VERSION 5.7 ;
  NOWIREEXTENSIONATPIN ON ;
  DIVIDERCHAR "/" ;
  BUSBITCHARS "[]" ;
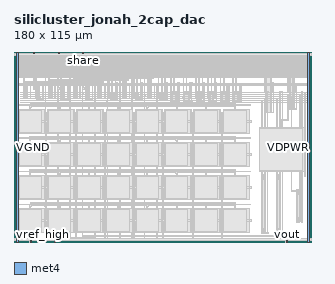
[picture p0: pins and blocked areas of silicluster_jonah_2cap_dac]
MACRO silicluster_jonah_2cap_dac
  CLASS BLOCK ;
  FOREIGN silicluster_jonah_2cap_dac ;
  ORIGIN 0.000 0.000 ;
  SIZE 180.000 BY 115.000 ;
  PIN VGND
    DIRECTION INPUT ;
    USE GROUND ;
    PORT
      LAYER met4 ;
        RECT 1.400 0.000 2.600 115.000 ;
    END
  END VGND
  PIN VDPWR
    DIRECTION INPUT ;
    USE POWER ;
    PORT
      LAYER met4 ;
        RECT 177.400 0.000 178.600 115.000 ;
    END
  END VDPWR
  PIN charge_high
    DIRECTION INPUT ;
    USE SIGNAL ;
    ANTENNAGATEAREA 0.600000 ;
    PORT
      LAYER met4 ;
        RECT 11.700 114.200 12.300 115.000 ;
    END
  END charge_high
  PIN charge_low
    DIRECTION INPUT ;
    USE SIGNAL ;
    ANTENNAGATEAREA 0.600000 ;
    PORT
      LAYER met4 ;
        RECT 26.700 114.200 27.300 115.000 ;
    END
  END charge_low
  PIN share
    DIRECTION INPUT ;
    USE SIGNAL ;
    ANTENNAGATEAREA 0.600000 ;
    PORT
      LAYER met4 ;
        RECT 41.700 114.200 42.300 115.000 ;
    END
  END share
  PIN vref_high
    DIRECTION INPUT ;
    USE SIGNAL ;
    ANTENNADIFFAREA 0.870000 ;
    PORT
      LAYER met4 ;
        RECT 9.700 0.000 10.300 0.800 ;
    END
  END vref_high
  PIN vref_low
    DIRECTION INPUT ;
    USE SIGNAL ;
    ANTENNADIFFAREA 0.870000 ;
    PORT
      LAYER met4 ;
        RECT 24.700 0.000 25.300 0.800 ;
    END
  END vref_low
  PIN vout
    DIRECTION OUTPUT ;
    USE SIGNAL ;
    ANTENNAGATEAREA 4.000000 ;
    ANTENNADIFFAREA 12.759999 ;
    PORT
      LAYER met4 ;
        RECT 164.700 0.000 165.300 0.800 ;
    END
  END vout
  OBS
      LAYER pwell ;
        RECT 5.945 86.605 8.055 89.395 ;
      LAYER nwell ;
        RECT 13.445 86.080 15.555 89.920 ;
      LAYER pwell ;
        RECT 20.945 86.605 23.055 89.395 ;
      LAYER nwell ;
        RECT 28.445 86.080 30.555 89.920 ;
      LAYER pwell ;
        RECT 35.945 86.605 38.055 89.395 ;
      LAYER nwell ;
        RECT 43.445 86.080 45.555 89.920 ;
      LAYER pwell ;
        RECT 50.945 86.605 53.055 89.395 ;
      LAYER nwell ;
        RECT 58.345 86.080 60.655 89.920 ;
      LAYER pwell ;
        RECT 65.945 86.605 68.055 89.395 ;
      LAYER nwell ;
        RECT 73.345 86.080 75.655 89.920 ;
      LAYER pwell ;
        RECT 80.945 86.605 83.055 89.395 ;
      LAYER nwell ;
        RECT 88.345 86.080 90.655 89.920 ;
        RECT 95.020 85.080 98.980 90.920 ;
        RECT 102.520 85.080 106.480 90.920 ;
        RECT 110.520 85.080 113.480 90.920 ;
        RECT 118.020 85.080 120.980 90.920 ;
      LAYER pwell ;
        RECT 125.020 85.105 128.980 90.895 ;
        RECT 132.520 85.105 136.480 90.895 ;
      LAYER nwell ;
        RECT 152.020 78.080 155.980 103.920 ;
      LAYER pwell ;
        RECT 166.520 80.105 169.480 101.895 ;
        RECT 149.995 5.090 152.005 40.910 ;
        RECT 158.995 5.090 161.005 40.910 ;
        RECT 170.995 12.090 173.005 31.910 ;
      LAYER li1 ;
        RECT 152.200 103.570 155.800 103.740 ;
        RECT 95.200 90.570 98.800 90.740 ;
        RECT 13.625 89.570 15.375 89.740 ;
        RECT 6.125 89.045 7.875 89.215 ;
        RECT 6.125 86.955 6.295 89.045 ;
        RECT 6.835 88.535 7.165 88.705 ;
        RECT 6.695 87.325 6.865 88.365 ;
        RECT 7.135 87.325 7.305 88.365 ;
        RECT 7.705 86.955 7.875 89.045 ;
        RECT 6.125 86.785 7.875 86.955 ;
        RECT 13.625 86.430 13.795 89.570 ;
        RECT 14.335 89.055 14.665 89.225 ;
        RECT 14.195 86.800 14.365 88.840 ;
        RECT 14.635 86.800 14.805 88.840 ;
        RECT 15.205 86.430 15.375 89.570 ;
        RECT 28.625 89.570 30.375 89.740 ;
        RECT 21.125 89.045 22.875 89.215 ;
        RECT 21.125 86.955 21.295 89.045 ;
        RECT 21.835 88.535 22.165 88.705 ;
        RECT 21.695 87.325 21.865 88.365 ;
        RECT 22.135 87.325 22.305 88.365 ;
        RECT 22.705 86.955 22.875 89.045 ;
        RECT 21.125 86.785 22.875 86.955 ;
        RECT 13.625 86.260 15.375 86.430 ;
        RECT 28.625 86.430 28.795 89.570 ;
        RECT 29.335 89.055 29.665 89.225 ;
        RECT 29.195 86.800 29.365 88.840 ;
        RECT 29.635 86.800 29.805 88.840 ;
        RECT 30.205 86.430 30.375 89.570 ;
        RECT 43.625 89.570 45.375 89.740 ;
        RECT 36.125 89.045 37.875 89.215 ;
        RECT 36.125 86.955 36.295 89.045 ;
        RECT 36.835 88.535 37.165 88.705 ;
        RECT 36.695 87.325 36.865 88.365 ;
        RECT 37.135 87.325 37.305 88.365 ;
        RECT 37.705 86.955 37.875 89.045 ;
        RECT 36.125 86.785 37.875 86.955 ;
        RECT 28.625 86.260 30.375 86.430 ;
        RECT 43.625 86.430 43.795 89.570 ;
        RECT 44.335 89.055 44.665 89.225 ;
        RECT 44.195 86.800 44.365 88.840 ;
        RECT 44.635 86.800 44.805 88.840 ;
        RECT 45.205 86.430 45.375 89.570 ;
        RECT 58.525 89.570 60.475 89.740 ;
        RECT 51.125 89.045 52.875 89.215 ;
        RECT 51.125 86.955 51.295 89.045 ;
        RECT 51.835 88.535 52.165 88.705 ;
        RECT 51.695 87.325 51.865 88.365 ;
        RECT 52.135 87.325 52.305 88.365 ;
        RECT 52.705 86.955 52.875 89.045 ;
        RECT 51.125 86.785 52.875 86.955 ;
        RECT 43.625 86.260 45.375 86.430 ;
        RECT 58.525 86.430 58.695 89.570 ;
        RECT 59.325 89.055 59.675 89.225 ;
        RECT 59.095 86.800 59.265 88.840 ;
        RECT 59.735 86.800 59.905 88.840 ;
        RECT 60.305 86.430 60.475 89.570 ;
        RECT 73.525 89.570 75.475 89.740 ;
        RECT 66.125 89.045 67.875 89.215 ;
        RECT 66.125 86.955 66.295 89.045 ;
        RECT 66.835 88.535 67.165 88.705 ;
        RECT 66.695 87.325 66.865 88.365 ;
        RECT 67.135 87.325 67.305 88.365 ;
        RECT 67.705 86.955 67.875 89.045 ;
        RECT 66.125 86.785 67.875 86.955 ;
        RECT 58.525 86.260 60.475 86.430 ;
        RECT 73.525 86.430 73.695 89.570 ;
        RECT 74.325 89.055 74.675 89.225 ;
        RECT 74.095 86.800 74.265 88.840 ;
        RECT 74.735 86.800 74.905 88.840 ;
        RECT 75.305 86.430 75.475 89.570 ;
        RECT 88.525 89.570 90.475 89.740 ;
        RECT 81.125 89.045 82.875 89.215 ;
        RECT 81.125 86.955 81.295 89.045 ;
        RECT 81.835 88.535 82.165 88.705 ;
        RECT 81.695 87.325 81.865 88.365 ;
        RECT 82.135 87.325 82.305 88.365 ;
        RECT 82.705 86.955 82.875 89.045 ;
        RECT 81.125 86.785 82.875 86.955 ;
        RECT 73.525 86.260 75.475 86.430 ;
        RECT 88.525 86.430 88.695 89.570 ;
        RECT 89.325 89.055 89.675 89.225 ;
        RECT 89.095 86.800 89.265 88.840 ;
        RECT 89.735 86.800 89.905 88.840 ;
        RECT 90.305 86.430 90.475 89.570 ;
        RECT 88.525 86.260 90.475 86.430 ;
        RECT 95.200 85.430 95.370 90.570 ;
        RECT 96.000 90.055 98.000 90.225 ;
        RECT 95.770 85.800 95.940 89.840 ;
        RECT 98.060 85.800 98.230 89.840 ;
        RECT 98.630 85.430 98.800 90.570 ;
        RECT 95.200 85.260 98.800 85.430 ;
        RECT 102.700 90.570 106.300 90.740 ;
        RECT 102.700 85.430 102.870 90.570 ;
        RECT 103.500 90.055 105.500 90.225 ;
        RECT 103.270 85.800 103.440 89.840 ;
        RECT 105.560 85.800 105.730 89.840 ;
        RECT 106.130 85.430 106.300 90.570 ;
        RECT 102.700 85.260 106.300 85.430 ;
        RECT 110.700 90.570 113.300 90.740 ;
        RECT 110.700 85.430 110.870 90.570 ;
        RECT 111.500 90.055 112.500 90.225 ;
        RECT 111.270 85.800 111.440 89.840 ;
        RECT 112.560 85.800 112.730 89.840 ;
        RECT 113.130 85.430 113.300 90.570 ;
        RECT 110.700 85.260 113.300 85.430 ;
        RECT 118.200 90.570 120.800 90.740 ;
        RECT 118.200 85.430 118.370 90.570 ;
        RECT 119.000 90.055 120.000 90.225 ;
        RECT 118.770 85.800 118.940 89.840 ;
        RECT 120.060 85.800 120.230 89.840 ;
        RECT 120.630 85.430 120.800 90.570 ;
        RECT 118.200 85.260 120.800 85.430 ;
        RECT 125.200 90.545 128.800 90.715 ;
        RECT 125.200 85.455 125.370 90.545 ;
        RECT 126.000 90.035 128.000 90.205 ;
        RECT 125.770 85.825 125.940 89.865 ;
        RECT 128.060 85.825 128.230 89.865 ;
        RECT 128.630 85.455 128.800 90.545 ;
        RECT 125.200 85.285 128.800 85.455 ;
        RECT 132.700 90.545 136.300 90.715 ;
        RECT 132.700 85.455 132.870 90.545 ;
        RECT 133.500 90.035 135.500 90.205 ;
        RECT 133.270 85.825 133.440 89.865 ;
        RECT 135.560 85.825 135.730 89.865 ;
        RECT 136.130 85.455 136.300 90.545 ;
        RECT 132.700 85.285 136.300 85.455 ;
        RECT 152.200 78.430 152.370 103.570 ;
        RECT 153.000 103.055 155.000 103.225 ;
        RECT 152.770 78.800 152.940 102.840 ;
        RECT 155.060 78.800 155.230 102.840 ;
        RECT 155.630 78.430 155.800 103.570 ;
        RECT 166.700 101.545 169.300 101.715 ;
        RECT 166.700 80.455 166.870 101.545 ;
        RECT 167.500 101.035 168.500 101.205 ;
        RECT 167.270 80.825 167.440 100.865 ;
        RECT 168.560 80.825 168.730 100.865 ;
        RECT 169.130 80.455 169.300 101.545 ;
        RECT 166.700 80.285 169.300 80.455 ;
        RECT 152.200 78.260 155.800 78.430 ;
        RECT 150.175 40.560 151.825 40.730 ;
        RECT 150.175 5.440 150.345 40.560 ;
        RECT 150.825 37.920 151.175 40.080 ;
        RECT 150.825 5.920 151.175 8.080 ;
        RECT 151.655 5.440 151.825 40.560 ;
        RECT 150.175 5.270 151.825 5.440 ;
        RECT 159.175 40.560 160.825 40.730 ;
        RECT 159.175 5.440 159.345 40.560 ;
        RECT 159.825 37.920 160.175 40.080 ;
        RECT 159.825 5.920 160.175 8.080 ;
        RECT 160.655 5.440 160.825 40.560 ;
        RECT 171.175 31.560 172.825 31.730 ;
        RECT 171.175 12.440 171.345 31.560 ;
        RECT 171.825 28.920 172.175 31.080 ;
        RECT 171.825 12.920 172.175 15.080 ;
        RECT 172.655 12.440 172.825 31.560 ;
        RECT 171.175 12.270 172.825 12.440 ;
        RECT 159.175 5.270 160.825 5.440 ;
      LAYER met1 ;
        RECT 41.250 113.750 41.750 114.250 ;
        RECT 26.250 106.750 26.750 107.250 ;
        RECT 18.750 104.750 19.250 105.250 ;
        RECT 14.250 89.490 14.750 89.990 ;
        RECT 6.750 88.970 7.250 89.470 ;
        RECT 14.370 89.255 14.630 89.490 ;
        RECT 14.355 89.025 14.645 89.255 ;
        RECT 14.370 89.010 14.630 89.025 ;
        RECT 6.870 88.735 7.130 88.970 ;
        RECT 6.855 88.505 7.145 88.735 ;
        RECT 6.870 88.490 7.130 88.505 ;
        RECT 5.750 87.985 6.250 88.095 ;
        RECT 6.665 87.985 6.895 88.345 ;
        RECT 7.105 87.985 7.335 88.345 ;
        RECT 7.750 87.985 8.250 88.095 ;
        RECT 5.750 87.705 6.920 87.985 ;
        RECT 7.080 87.705 8.250 87.985 ;
        RECT 5.750 87.595 6.250 87.705 ;
        RECT 6.665 87.345 6.895 87.705 ;
        RECT 7.105 87.345 7.335 87.705 ;
        RECT 7.750 87.595 8.250 87.705 ;
        RECT 13.250 87.960 13.750 88.070 ;
        RECT 14.165 87.960 14.395 88.820 ;
        RECT 14.605 87.960 14.835 88.820 ;
        RECT 15.250 87.960 15.750 88.070 ;
        RECT 13.250 87.680 14.420 87.960 ;
        RECT 14.580 87.680 15.750 87.960 ;
        RECT 13.250 87.570 13.750 87.680 ;
        RECT 6.750 87.010 7.250 87.120 ;
        RECT 9.750 87.010 10.250 87.120 ;
        RECT 6.750 86.730 10.250 87.010 ;
        RECT 14.165 86.820 14.395 87.680 ;
        RECT 14.605 86.820 14.835 87.680 ;
        RECT 15.250 87.570 15.750 87.680 ;
        RECT 6.750 86.620 7.250 86.730 ;
        RECT 9.750 86.620 10.250 86.730 ;
        RECT 14.250 86.485 14.750 86.595 ;
        RECT 17.250 86.485 17.750 86.595 ;
        RECT 14.250 86.205 17.750 86.485 ;
        RECT 14.250 86.095 14.750 86.205 ;
        RECT 17.250 86.095 17.750 86.205 ;
        RECT 18.800 82.250 19.200 104.750 ;
        RECT 21.750 88.970 22.250 89.470 ;
        RECT 21.870 88.735 22.130 88.970 ;
        RECT 21.855 88.505 22.145 88.735 ;
        RECT 21.870 88.490 22.130 88.505 ;
        RECT 20.750 87.985 21.250 88.095 ;
        RECT 21.665 87.985 21.895 88.345 ;
        RECT 22.105 87.985 22.335 88.345 ;
        RECT 22.750 87.985 23.250 88.095 ;
        RECT 20.750 87.705 21.920 87.985 ;
        RECT 22.080 87.705 23.250 87.985 ;
        RECT 20.750 87.595 21.250 87.705 ;
        RECT 21.665 87.345 21.895 87.705 ;
        RECT 22.105 87.345 22.335 87.705 ;
        RECT 22.750 87.595 23.250 87.705 ;
        RECT 21.750 87.010 22.250 87.120 ;
        RECT 24.750 87.010 25.250 87.120 ;
        RECT 21.750 86.730 25.250 87.010 ;
        RECT 21.750 86.620 22.250 86.730 ;
        RECT 24.750 86.620 25.250 86.730 ;
        RECT 26.300 83.750 26.700 106.750 ;
        RECT 33.750 102.750 34.250 103.250 ;
        RECT 29.250 89.490 29.750 89.990 ;
        RECT 29.370 89.255 29.630 89.490 ;
        RECT 29.355 89.025 29.645 89.255 ;
        RECT 29.370 89.010 29.630 89.025 ;
        RECT 28.250 87.960 28.750 88.070 ;
        RECT 29.165 87.960 29.395 88.820 ;
        RECT 29.605 87.960 29.835 88.820 ;
        RECT 30.250 87.960 30.750 88.070 ;
        RECT 28.250 87.680 29.420 87.960 ;
        RECT 29.580 87.680 30.750 87.960 ;
        RECT 28.250 87.570 28.750 87.680 ;
        RECT 29.165 86.820 29.395 87.680 ;
        RECT 29.605 86.820 29.835 87.680 ;
        RECT 30.250 87.570 30.750 87.680 ;
        RECT 29.250 86.485 29.750 86.595 ;
        RECT 32.250 86.485 32.750 86.595 ;
        RECT 29.250 86.205 32.750 86.485 ;
        RECT 29.250 86.095 29.750 86.205 ;
        RECT 32.250 86.095 32.750 86.205 ;
        RECT 26.250 83.250 26.750 83.750 ;
        RECT 18.750 81.750 19.250 82.250 ;
        RECT 18.800 62.250 19.200 81.750 ;
        RECT 26.300 63.750 26.700 83.250 ;
        RECT 26.250 63.250 26.750 63.750 ;
        RECT 18.750 61.750 19.250 62.250 ;
        RECT 18.800 42.250 19.200 61.750 ;
        RECT 26.300 43.750 26.700 63.250 ;
        RECT 26.250 43.250 26.750 43.750 ;
        RECT 18.750 41.750 19.250 42.250 ;
        RECT 18.800 22.250 19.200 41.750 ;
        RECT 26.300 23.750 26.700 43.250 ;
        RECT 26.250 23.250 26.750 23.750 ;
        RECT 18.750 21.750 19.250 22.250 ;
        RECT 18.800 1.000 19.200 21.750 ;
        RECT 26.300 1.000 26.700 23.250 ;
        RECT 33.800 2.050 34.200 102.750 ;
        RECT 41.300 89.550 41.700 113.750 ;
        RECT 78.750 112.750 79.250 113.250 ;
        RECT 71.250 111.750 71.750 112.250 ;
        RECT 63.750 108.750 64.250 109.250 ;
        RECT 56.250 107.750 56.750 108.250 ;
        RECT 48.750 103.750 49.250 104.250 ;
        RECT 36.750 88.970 37.250 89.470 ;
        RECT 41.250 89.050 41.750 89.550 ;
        RECT 44.250 89.490 44.750 89.990 ;
        RECT 44.370 89.255 44.630 89.490 ;
        RECT 36.870 88.735 37.130 88.970 ;
        RECT 36.855 88.505 37.145 88.735 ;
        RECT 36.870 88.490 37.130 88.505 ;
        RECT 35.750 87.985 36.250 88.095 ;
        RECT 36.665 87.985 36.895 88.345 ;
        RECT 37.105 87.985 37.335 88.345 ;
        RECT 37.750 87.985 38.250 88.095 ;
        RECT 35.750 87.705 36.920 87.985 ;
        RECT 37.080 87.705 38.250 87.985 ;
        RECT 35.750 87.595 36.250 87.705 ;
        RECT 36.665 87.345 36.895 87.705 ;
        RECT 37.105 87.345 37.335 87.705 ;
        RECT 37.750 87.595 38.250 87.705 ;
        RECT 36.750 87.010 37.250 87.120 ;
        RECT 39.750 87.010 40.250 87.120 ;
        RECT 36.750 86.730 40.250 87.010 ;
        RECT 36.750 86.620 37.250 86.730 ;
        RECT 39.750 86.620 40.250 86.730 ;
        RECT 41.300 4.050 41.700 89.050 ;
        RECT 44.355 89.025 44.645 89.255 ;
        RECT 44.370 89.010 44.630 89.025 ;
        RECT 43.250 87.960 43.750 88.070 ;
        RECT 44.165 87.960 44.395 88.820 ;
        RECT 44.605 87.960 44.835 88.820 ;
        RECT 45.250 87.960 45.750 88.070 ;
        RECT 43.250 87.680 44.420 87.960 ;
        RECT 44.580 87.680 45.750 87.960 ;
        RECT 43.250 87.570 43.750 87.680 ;
        RECT 44.165 86.820 44.395 87.680 ;
        RECT 44.605 86.820 44.835 87.680 ;
        RECT 45.250 87.570 45.750 87.680 ;
        RECT 44.250 86.485 44.750 86.595 ;
        RECT 47.250 86.485 47.750 86.595 ;
        RECT 44.250 86.205 47.750 86.485 ;
        RECT 44.250 86.095 44.750 86.205 ;
        RECT 47.250 86.095 47.750 86.205 ;
        RECT 41.250 3.550 41.750 4.050 ;
        RECT 33.750 1.550 34.250 2.050 ;
        RECT 33.800 1.000 34.200 1.550 ;
        RECT 41.300 1.000 41.700 3.550 ;
        RECT 48.800 3.050 49.200 103.750 ;
        RECT 51.750 88.970 52.250 89.470 ;
        RECT 51.870 88.735 52.130 88.970 ;
        RECT 51.855 88.505 52.145 88.735 ;
        RECT 51.870 88.490 52.130 88.505 ;
        RECT 50.750 87.985 51.250 88.095 ;
        RECT 51.665 87.985 51.895 88.345 ;
        RECT 52.105 87.985 52.335 88.345 ;
        RECT 52.750 87.985 53.250 88.095 ;
        RECT 50.750 87.705 51.920 87.985 ;
        RECT 52.080 87.705 53.250 87.985 ;
        RECT 50.750 87.595 51.250 87.705 ;
        RECT 51.665 87.345 51.895 87.705 ;
        RECT 52.105 87.345 52.335 87.705 ;
        RECT 52.750 87.595 53.250 87.705 ;
        RECT 51.750 87.010 52.250 87.120 ;
        RECT 54.750 87.010 55.250 87.120 ;
        RECT 51.750 86.730 55.250 87.010 ;
        RECT 51.750 86.620 52.250 86.730 ;
        RECT 54.750 86.620 55.250 86.730 ;
        RECT 56.300 84.750 56.700 107.750 ;
        RECT 59.250 89.490 59.750 89.990 ;
        RECT 59.370 89.255 59.630 89.490 ;
        RECT 59.345 89.025 59.655 89.255 ;
        RECT 59.370 89.010 59.630 89.025 ;
        RECT 57.250 87.960 57.750 88.070 ;
        RECT 59.065 87.960 59.295 88.820 ;
        RECT 59.705 87.960 59.935 88.820 ;
        RECT 61.250 87.960 61.750 88.070 ;
        RECT 57.250 87.680 59.320 87.960 ;
        RECT 59.680 87.680 61.750 87.960 ;
        RECT 57.250 87.570 57.750 87.680 ;
        RECT 59.065 86.820 59.295 87.680 ;
        RECT 59.705 86.820 59.935 87.680 ;
        RECT 61.250 87.570 61.750 87.680 ;
        RECT 59.250 86.485 59.750 86.595 ;
        RECT 62.250 86.485 62.750 86.595 ;
        RECT 59.250 86.205 62.750 86.485 ;
        RECT 59.250 86.095 59.750 86.205 ;
        RECT 62.250 86.095 62.750 86.205 ;
        RECT 63.800 85.950 64.200 108.750 ;
        RECT 66.750 88.970 67.250 89.470 ;
        RECT 66.870 88.735 67.130 88.970 ;
        RECT 66.855 88.505 67.145 88.735 ;
        RECT 66.870 88.490 67.130 88.505 ;
        RECT 65.750 87.985 66.250 88.095 ;
        RECT 66.665 87.985 66.895 88.345 ;
        RECT 67.105 87.985 67.335 88.345 ;
        RECT 67.750 87.985 68.250 88.095 ;
        RECT 65.750 87.705 66.920 87.985 ;
        RECT 67.080 87.705 68.250 87.985 ;
        RECT 65.750 87.595 66.250 87.705 ;
        RECT 66.665 87.345 66.895 87.705 ;
        RECT 67.105 87.345 67.335 87.705 ;
        RECT 67.750 87.595 68.250 87.705 ;
        RECT 71.300 87.150 71.700 111.750 ;
        RECT 74.250 89.490 74.750 89.990 ;
        RECT 74.370 89.255 74.630 89.490 ;
        RECT 74.345 89.025 74.655 89.255 ;
        RECT 74.370 89.010 74.630 89.025 ;
        RECT 72.250 87.960 72.750 88.070 ;
        RECT 74.065 87.960 74.295 88.820 ;
        RECT 74.705 87.960 74.935 88.820 ;
        RECT 78.800 88.350 79.200 112.750 ;
        RECT 153.750 103.490 154.250 103.990 ;
        RECT 153.870 103.255 154.130 103.490 ;
        RECT 153.020 103.025 154.980 103.255 ;
        RECT 153.870 103.010 154.130 103.025 ;
        RECT 86.250 94.750 86.750 95.250 ;
        RECT 86.300 90.750 86.700 94.750 ;
        RECT 86.250 90.250 86.750 90.750 ;
        RECT 96.750 90.490 97.250 90.990 ;
        RECT 104.250 90.490 104.750 90.990 ;
        RECT 111.750 90.490 112.250 90.990 ;
        RECT 119.250 90.490 119.750 90.990 ;
        RECT 96.870 90.255 97.130 90.490 ;
        RECT 104.370 90.255 104.630 90.490 ;
        RECT 111.870 90.255 112.130 90.490 ;
        RECT 119.370 90.255 119.630 90.490 ;
        RECT 126.750 90.470 127.250 90.970 ;
        RECT 134.250 90.470 134.750 90.970 ;
        RECT 151.750 90.960 152.250 91.070 ;
        RECT 152.740 90.960 152.970 102.820 ;
        RECT 155.030 90.960 155.260 102.820 ;
        RECT 167.750 101.470 168.250 101.970 ;
        RECT 167.870 101.235 168.130 101.470 ;
        RECT 167.520 101.005 168.480 101.235 ;
        RECT 167.870 100.990 168.130 101.005 ;
        RECT 155.750 90.960 156.250 91.070 ;
        RECT 151.750 90.680 152.995 90.960 ;
        RECT 155.005 90.680 156.250 90.960 ;
        RECT 151.750 90.570 152.250 90.680 ;
        RECT 81.750 88.970 82.250 89.470 ;
        RECT 81.870 88.735 82.130 88.970 ;
        RECT 81.855 88.505 82.145 88.735 ;
        RECT 81.870 88.490 82.130 88.505 ;
        RECT 76.250 87.960 76.750 88.070 ;
        RECT 72.250 87.680 74.320 87.960 ;
        RECT 74.680 87.680 76.750 87.960 ;
        RECT 78.750 87.850 79.250 88.350 ;
        RECT 80.750 87.985 81.250 88.095 ;
        RECT 81.665 87.985 81.895 88.345 ;
        RECT 82.105 87.985 82.335 88.345 ;
        RECT 82.750 87.985 83.250 88.095 ;
        RECT 72.250 87.570 72.750 87.680 ;
        RECT 66.750 87.010 67.250 87.120 ;
        RECT 69.750 87.010 70.250 87.120 ;
        RECT 66.750 86.730 70.250 87.010 ;
        RECT 66.750 86.620 67.250 86.730 ;
        RECT 69.750 86.620 70.250 86.730 ;
        RECT 71.250 86.650 71.750 87.150 ;
        RECT 74.065 86.820 74.295 87.680 ;
        RECT 74.705 86.820 74.935 87.680 ;
        RECT 76.250 87.570 76.750 87.680 ;
        RECT 63.750 85.450 64.250 85.950 ;
        RECT 56.250 84.250 56.750 84.750 ;
        RECT 48.750 2.550 49.250 3.050 ;
        RECT 48.800 1.000 49.200 2.550 ;
        RECT 56.300 1.000 56.700 84.250 ;
        RECT 63.800 1.000 64.200 85.450 ;
        RECT 71.300 1.000 71.700 86.650 ;
        RECT 74.250 86.485 74.750 86.595 ;
        RECT 77.250 86.485 77.750 86.595 ;
        RECT 74.250 86.205 77.750 86.485 ;
        RECT 74.250 86.095 74.750 86.205 ;
        RECT 77.250 86.095 77.750 86.205 ;
        RECT 78.800 1.000 79.200 87.850 ;
        RECT 80.750 87.705 81.920 87.985 ;
        RECT 82.080 87.705 83.250 87.985 ;
        RECT 80.750 87.595 81.250 87.705 ;
        RECT 81.665 87.345 81.895 87.705 ;
        RECT 82.105 87.345 82.335 87.705 ;
        RECT 82.750 87.595 83.250 87.705 ;
        RECT 81.750 87.010 82.250 87.120 ;
        RECT 84.750 87.010 85.250 87.120 ;
        RECT 81.750 86.730 85.250 87.010 ;
        RECT 81.750 86.620 82.250 86.730 ;
        RECT 84.750 86.620 85.250 86.730 ;
        RECT 86.300 83.000 86.700 90.250 ;
        RECT 96.020 90.025 97.980 90.255 ;
        RECT 103.520 90.025 105.480 90.255 ;
        RECT 111.520 90.025 112.480 90.255 ;
        RECT 119.020 90.025 119.980 90.255 ;
        RECT 126.870 90.235 127.130 90.470 ;
        RECT 134.370 90.235 134.630 90.470 ;
        RECT 96.870 90.010 97.130 90.025 ;
        RECT 104.370 90.010 104.630 90.025 ;
        RECT 111.870 90.010 112.130 90.025 ;
        RECT 119.370 90.010 119.630 90.025 ;
        RECT 126.020 90.005 127.980 90.235 ;
        RECT 133.520 90.005 135.480 90.235 ;
        RECT 126.870 89.990 127.130 90.005 ;
        RECT 134.370 89.990 134.630 90.005 ;
        RECT 89.250 89.490 89.750 89.990 ;
        RECT 89.370 89.255 89.630 89.490 ;
        RECT 89.345 89.025 89.655 89.255 ;
        RECT 89.370 89.010 89.630 89.025 ;
        RECT 87.250 87.960 87.750 88.070 ;
        RECT 89.065 87.960 89.295 88.820 ;
        RECT 89.705 87.960 89.935 88.820 ;
        RECT 91.250 87.960 91.750 88.070 ;
        RECT 87.250 87.680 89.320 87.960 ;
        RECT 89.680 87.680 91.750 87.960 ;
        RECT 87.250 87.570 87.750 87.680 ;
        RECT 89.065 86.820 89.295 87.680 ;
        RECT 89.705 86.820 89.935 87.680 ;
        RECT 91.250 87.570 91.750 87.680 ;
        RECT 94.750 87.960 95.250 88.070 ;
        RECT 95.740 87.960 95.970 89.820 ;
        RECT 98.030 87.960 98.260 89.820 ;
        RECT 98.750 87.960 99.250 88.070 ;
        RECT 94.750 87.680 95.995 87.960 ;
        RECT 98.005 87.680 99.250 87.960 ;
        RECT 94.750 87.570 95.250 87.680 ;
        RECT 89.250 86.485 89.750 86.595 ;
        RECT 92.250 86.485 92.750 86.595 ;
        RECT 89.250 86.205 92.750 86.485 ;
        RECT 89.250 86.095 89.750 86.205 ;
        RECT 92.250 86.095 92.750 86.205 ;
        RECT 95.740 85.820 95.970 87.680 ;
        RECT 98.030 85.820 98.260 87.680 ;
        RECT 98.750 87.570 99.250 87.680 ;
        RECT 102.250 87.960 102.750 88.070 ;
        RECT 103.240 87.960 103.470 89.820 ;
        RECT 105.530 87.960 105.760 89.820 ;
        RECT 106.250 87.960 106.750 88.070 ;
        RECT 102.250 87.680 103.495 87.960 ;
        RECT 105.505 87.680 106.750 87.960 ;
        RECT 102.250 87.570 102.750 87.680 ;
        RECT 103.240 85.820 103.470 87.680 ;
        RECT 105.530 85.820 105.760 87.680 ;
        RECT 106.250 87.570 106.750 87.680 ;
        RECT 109.750 87.960 110.250 88.070 ;
        RECT 111.240 87.960 111.470 89.820 ;
        RECT 112.530 87.960 112.760 89.820 ;
        RECT 113.750 87.960 114.250 88.070 ;
        RECT 109.750 87.680 111.495 87.960 ;
        RECT 112.505 87.680 114.250 87.960 ;
        RECT 109.750 87.570 110.250 87.680 ;
        RECT 111.240 85.820 111.470 87.680 ;
        RECT 112.530 85.820 112.760 87.680 ;
        RECT 113.750 87.570 114.250 87.680 ;
        RECT 117.250 87.960 117.750 88.070 ;
        RECT 118.740 87.960 118.970 89.820 ;
        RECT 120.030 87.960 120.260 89.820 ;
        RECT 121.250 87.960 121.750 88.070 ;
        RECT 117.250 87.680 118.995 87.960 ;
        RECT 120.005 87.680 121.750 87.960 ;
        RECT 117.250 87.570 117.750 87.680 ;
        RECT 118.740 85.820 118.970 87.680 ;
        RECT 120.030 85.820 120.260 87.680 ;
        RECT 121.250 87.570 121.750 87.680 ;
        RECT 124.750 87.985 125.250 88.095 ;
        RECT 125.740 87.985 125.970 89.845 ;
        RECT 128.030 87.985 128.260 89.845 ;
        RECT 128.750 87.985 129.250 88.095 ;
        RECT 124.750 87.705 125.995 87.985 ;
        RECT 128.005 87.705 129.250 87.985 ;
        RECT 124.750 87.595 125.250 87.705 ;
        RECT 125.740 85.845 125.970 87.705 ;
        RECT 128.030 85.845 128.260 87.705 ;
        RECT 128.750 87.595 129.250 87.705 ;
        RECT 132.250 87.985 132.750 88.095 ;
        RECT 133.240 87.985 133.470 89.845 ;
        RECT 135.530 87.985 135.760 89.845 ;
        RECT 136.250 87.985 136.750 88.095 ;
        RECT 132.250 87.705 133.495 87.985 ;
        RECT 135.505 87.705 136.750 87.985 ;
        RECT 132.250 87.595 132.750 87.705 ;
        RECT 133.240 85.845 133.470 87.705 ;
        RECT 135.530 85.845 135.760 87.705 ;
        RECT 136.250 87.595 136.750 87.705 ;
        RECT 96.750 85.485 97.250 85.595 ;
        RECT 99.750 85.485 100.250 85.595 ;
        RECT 96.750 85.205 100.250 85.485 ;
        RECT 96.750 85.095 97.250 85.205 ;
        RECT 99.750 85.095 100.250 85.205 ;
        RECT 104.250 85.485 104.750 85.595 ;
        RECT 107.250 85.485 107.750 85.595 ;
        RECT 104.250 85.205 107.750 85.485 ;
        RECT 104.250 85.095 104.750 85.205 ;
        RECT 107.250 85.095 107.750 85.205 ;
        RECT 111.750 85.485 112.250 85.595 ;
        RECT 114.750 85.485 115.250 85.595 ;
        RECT 111.750 85.205 115.250 85.485 ;
        RECT 111.750 85.095 112.250 85.205 ;
        RECT 114.750 85.095 115.250 85.205 ;
        RECT 119.250 85.485 119.750 85.595 ;
        RECT 122.250 85.485 122.750 85.595 ;
        RECT 119.250 85.205 122.750 85.485 ;
        RECT 119.250 85.095 119.750 85.205 ;
        RECT 122.250 85.095 122.750 85.205 ;
        RECT 126.750 85.510 127.250 85.620 ;
        RECT 129.750 85.510 130.250 85.620 ;
        RECT 126.750 85.230 130.250 85.510 ;
        RECT 126.750 85.120 127.250 85.230 ;
        RECT 129.750 85.120 130.250 85.230 ;
        RECT 134.250 85.510 134.750 85.620 ;
        RECT 137.250 85.510 137.750 85.620 ;
        RECT 134.250 85.230 137.750 85.510 ;
        RECT 134.250 85.120 134.750 85.230 ;
        RECT 137.250 85.120 137.750 85.230 ;
        RECT 86.250 82.500 86.750 83.000 ;
        RECT 86.300 63.000 86.700 82.500 ;
        RECT 152.740 78.820 152.970 90.680 ;
        RECT 155.030 78.820 155.260 90.680 ;
        RECT 155.750 90.570 156.250 90.680 ;
        RECT 165.750 90.985 166.250 91.095 ;
        RECT 167.240 90.985 167.470 100.845 ;
        RECT 168.530 90.985 168.760 100.845 ;
        RECT 169.750 90.985 170.250 91.095 ;
        RECT 165.750 90.705 167.495 90.985 ;
        RECT 168.505 90.705 170.250 90.985 ;
        RECT 165.750 90.595 166.250 90.705 ;
        RECT 167.240 80.845 167.470 90.705 ;
        RECT 168.530 80.845 168.760 90.705 ;
        RECT 169.750 90.595 170.250 90.705 ;
        RECT 167.750 80.510 168.250 80.620 ;
        RECT 170.750 80.510 171.250 80.620 ;
        RECT 167.750 80.230 171.250 80.510 ;
        RECT 167.750 80.120 168.250 80.230 ;
        RECT 170.750 80.120 171.250 80.230 ;
        RECT 153.750 78.485 154.250 78.595 ;
        RECT 156.750 78.485 157.250 78.595 ;
        RECT 153.750 78.205 157.250 78.485 ;
        RECT 153.750 78.095 154.250 78.205 ;
        RECT 156.750 78.095 157.250 78.205 ;
        RECT 86.250 62.500 86.750 63.000 ;
        RECT 86.300 43.000 86.700 62.500 ;
        RECT 86.250 42.500 86.750 43.000 ;
        RECT 86.300 23.000 86.700 42.500 ;
        RECT 149.750 40.045 150.250 40.155 ;
        RECT 150.875 40.045 151.125 40.050 ;
        RECT 158.750 40.045 159.250 40.155 ;
        RECT 159.875 40.045 160.125 40.050 ;
        RECT 149.750 39.765 151.140 40.045 ;
        RECT 158.750 39.765 160.140 40.045 ;
        RECT 149.750 39.655 150.250 39.765 ;
        RECT 150.875 37.945 151.125 39.765 ;
        RECT 158.750 39.655 159.250 39.765 ;
        RECT 159.875 37.945 160.125 39.765 ;
        RECT 167.750 31.045 168.250 31.155 ;
        RECT 171.875 31.045 172.125 31.050 ;
        RECT 167.750 30.765 172.140 31.045 ;
        RECT 167.750 30.655 168.250 30.765 ;
        RECT 171.875 28.945 172.125 30.765 ;
        RECT 86.250 22.500 86.750 23.000 ;
        RECT 86.300 1.000 86.700 22.500 ;
        RECT 171.875 13.235 172.125 15.055 ;
        RECT 172.750 13.235 173.250 13.345 ;
        RECT 171.860 12.955 173.250 13.235 ;
        RECT 171.875 12.950 172.125 12.955 ;
        RECT 172.750 12.845 173.250 12.955 ;
        RECT 171.750 12.495 172.250 12.605 ;
        RECT 174.250 12.495 174.750 12.605 ;
        RECT 171.750 12.215 174.750 12.495 ;
        RECT 171.750 12.105 172.250 12.215 ;
        RECT 174.250 12.105 174.750 12.215 ;
        RECT 150.875 6.235 151.125 8.055 ;
        RECT 151.750 6.235 152.250 6.345 ;
        RECT 159.875 6.235 160.125 8.055 ;
        RECT 160.750 6.235 161.250 6.345 ;
        RECT 150.860 5.955 152.250 6.235 ;
        RECT 159.860 5.955 161.250 6.235 ;
        RECT 150.875 5.950 151.125 5.955 ;
        RECT 151.750 5.845 152.250 5.955 ;
        RECT 159.875 5.950 160.125 5.955 ;
        RECT 160.750 5.845 161.250 5.955 ;
        RECT 150.750 5.495 151.250 5.605 ;
        RECT 153.250 5.495 153.750 5.605 ;
        RECT 150.750 5.215 153.750 5.495 ;
        RECT 150.750 5.105 151.250 5.215 ;
        RECT 153.250 5.105 153.750 5.215 ;
        RECT 159.750 5.495 160.250 5.605 ;
        RECT 162.250 5.495 162.750 5.605 ;
        RECT 159.750 5.215 162.750 5.495 ;
        RECT 159.750 5.105 160.250 5.215 ;
        RECT 162.250 5.105 162.750 5.215 ;
      LAYER met2 ;
        RECT 41.200 113.700 41.800 114.300 ;
        RECT 119.200 113.700 119.800 114.300 ;
        RECT 151.700 113.700 152.300 114.300 ;
        RECT 165.700 113.700 166.300 114.300 ;
        RECT 78.700 112.700 79.300 113.300 ;
        RECT 71.200 111.700 71.800 112.300 ;
        RECT 109.700 111.700 110.300 112.300 ;
        RECT 102.200 110.700 102.800 111.300 ;
        RECT 63.700 108.700 64.300 109.300 ;
        RECT 56.200 107.700 56.800 108.300 ;
        RECT 94.700 107.700 95.300 108.300 ;
        RECT 96.700 107.700 97.300 108.300 ;
        RECT 26.200 106.700 26.800 107.300 ;
        RECT 82.700 106.700 83.300 107.300 ;
        RECT 91.200 106.700 91.800 107.300 ;
        RECT 18.700 104.700 19.300 105.300 ;
        RECT 52.700 104.700 53.300 105.300 ;
        RECT 61.200 104.700 61.800 105.300 ;
        RECT 67.700 104.700 68.300 105.300 ;
        RECT 76.200 104.700 76.800 105.300 ;
        RECT 80.700 104.700 81.300 105.300 ;
        RECT 48.700 103.700 49.300 104.300 ;
        RECT 33.700 102.700 34.300 103.300 ;
        RECT 50.700 102.700 51.300 103.300 ;
        RECT 35.700 101.700 36.300 102.300 ;
        RECT 43.200 101.700 43.800 102.300 ;
        RECT 20.700 100.700 21.300 101.300 ;
        RECT 28.200 100.700 28.800 101.300 ;
        RECT 5.700 99.700 6.300 100.300 ;
        RECT 13.200 99.700 13.800 100.300 ;
        RECT 5.800 88.095 6.200 99.700 ;
        RECT 6.700 96.700 7.300 97.300 ;
        RECT 11.700 96.700 12.300 97.300 ;
        RECT 6.800 89.470 7.200 96.700 ;
        RECT 7.700 94.700 8.300 95.300 ;
        RECT 9.700 94.700 10.300 95.300 ;
        RECT 6.750 88.970 7.250 89.470 ;
        RECT 7.800 88.095 8.200 94.700 ;
        RECT 5.750 87.595 6.250 88.095 ;
        RECT 7.750 87.595 8.250 88.095 ;
        RECT 9.800 87.120 10.200 94.700 ;
        RECT 11.800 93.300 12.200 96.700 ;
        RECT 11.700 92.700 12.300 93.300 ;
        RECT 13.300 88.070 13.700 99.700 ;
        RECT 14.200 96.700 14.800 97.300 ;
        RECT 14.300 89.990 14.700 96.700 ;
        RECT 15.200 95.700 15.800 96.300 ;
        RECT 17.200 95.700 17.800 96.300 ;
        RECT 14.250 89.490 14.750 89.990 ;
        RECT 15.300 88.070 15.700 95.700 ;
        RECT 13.250 87.570 13.750 88.070 ;
        RECT 15.250 87.570 15.750 88.070 ;
        RECT 9.750 86.620 10.250 87.120 ;
        RECT 17.300 86.595 17.700 95.700 ;
        RECT 20.800 88.095 21.200 100.700 ;
        RECT 21.700 97.700 22.300 98.300 ;
        RECT 26.700 97.700 27.300 98.300 ;
        RECT 21.800 89.470 22.200 97.700 ;
        RECT 22.700 94.700 23.300 95.300 ;
        RECT 24.700 94.700 25.300 95.300 ;
        RECT 21.750 88.970 22.250 89.470 ;
        RECT 22.800 88.095 23.200 94.700 ;
        RECT 20.750 87.595 21.250 88.095 ;
        RECT 22.750 87.595 23.250 88.095 ;
        RECT 24.800 87.120 25.200 94.700 ;
        RECT 26.800 93.300 27.200 97.700 ;
        RECT 26.700 92.700 27.300 93.300 ;
        RECT 28.300 88.070 28.700 100.700 ;
        RECT 29.200 97.700 29.800 98.300 ;
        RECT 29.300 89.990 29.700 97.700 ;
        RECT 30.200 95.700 30.800 96.300 ;
        RECT 32.200 95.700 32.800 96.300 ;
        RECT 29.250 89.490 29.750 89.990 ;
        RECT 30.300 88.070 30.700 95.700 ;
        RECT 28.250 87.570 28.750 88.070 ;
        RECT 30.250 87.570 30.750 88.070 ;
        RECT 24.750 86.620 25.250 87.120 ;
        RECT 32.300 86.595 32.700 95.700 ;
        RECT 35.800 88.095 36.200 101.700 ;
        RECT 36.700 98.700 37.300 99.300 ;
        RECT 41.700 98.700 42.300 99.300 ;
        RECT 36.800 89.470 37.200 98.700 ;
        RECT 37.700 94.700 38.300 95.300 ;
        RECT 39.700 94.700 40.300 95.300 ;
        RECT 36.750 88.970 37.250 89.470 ;
        RECT 37.800 88.095 38.200 94.700 ;
        RECT 35.750 87.595 36.250 88.095 ;
        RECT 37.750 87.595 38.250 88.095 ;
        RECT 39.800 87.120 40.200 94.700 ;
        RECT 41.800 93.300 42.200 98.700 ;
        RECT 41.700 92.700 42.300 93.300 ;
        RECT 41.200 89.000 41.800 89.600 ;
        RECT 43.300 88.070 43.700 101.700 ;
        RECT 44.200 98.700 44.800 99.300 ;
        RECT 44.300 89.990 44.700 98.700 ;
        RECT 45.200 95.700 45.800 96.300 ;
        RECT 47.200 95.700 47.800 96.300 ;
        RECT 44.250 89.490 44.750 89.990 ;
        RECT 45.300 88.070 45.700 95.700 ;
        RECT 43.250 87.570 43.750 88.070 ;
        RECT 45.250 87.570 45.750 88.070 ;
        RECT 39.750 86.620 40.250 87.120 ;
        RECT 47.300 86.595 47.700 95.700 ;
        RECT 50.800 88.095 51.200 102.700 ;
        RECT 51.700 96.700 52.300 97.300 ;
        RECT 51.800 89.470 52.200 96.700 ;
        RECT 51.750 88.970 52.250 89.470 ;
        RECT 52.800 88.095 53.200 104.700 ;
        RECT 57.200 102.700 57.800 103.300 ;
        RECT 54.700 94.700 55.300 95.300 ;
        RECT 50.750 87.595 51.250 88.095 ;
        RECT 52.750 87.595 53.250 88.095 ;
        RECT 54.800 87.120 55.200 94.700 ;
        RECT 57.300 88.070 57.700 102.700 ;
        RECT 59.200 99.700 59.800 100.300 ;
        RECT 59.300 89.990 59.700 99.700 ;
        RECT 59.250 89.490 59.750 89.990 ;
        RECT 61.300 88.070 61.700 104.700 ;
        RECT 65.700 103.700 66.300 104.300 ;
        RECT 62.200 95.700 62.800 96.300 ;
        RECT 57.250 87.570 57.750 88.070 ;
        RECT 61.250 87.570 61.750 88.070 ;
        RECT 54.750 86.620 55.250 87.120 ;
        RECT 62.300 86.595 62.700 95.700 ;
        RECT 65.800 88.095 66.200 103.700 ;
        RECT 66.700 97.700 67.300 98.300 ;
        RECT 66.800 89.470 67.200 97.700 ;
        RECT 66.750 88.970 67.250 89.470 ;
        RECT 67.800 88.095 68.200 104.700 ;
        RECT 72.200 103.700 72.800 104.300 ;
        RECT 69.700 94.700 70.300 95.300 ;
        RECT 65.750 87.595 66.250 88.095 ;
        RECT 67.750 87.595 68.250 88.095 ;
        RECT 69.800 87.120 70.200 94.700 ;
        RECT 72.300 88.070 72.700 103.700 ;
        RECT 74.200 100.700 74.800 101.300 ;
        RECT 74.300 89.990 74.700 100.700 ;
        RECT 74.250 89.490 74.750 89.990 ;
        RECT 76.300 88.070 76.700 104.700 ;
        RECT 77.200 95.700 77.800 96.300 ;
        RECT 72.250 87.570 72.750 88.070 ;
        RECT 76.250 87.570 76.750 88.070 ;
        RECT 69.750 86.620 70.250 87.120 ;
        RECT 71.200 86.600 71.800 87.200 ;
        RECT 77.300 86.595 77.700 95.700 ;
        RECT 78.700 87.800 79.300 88.400 ;
        RECT 80.800 88.095 81.200 104.700 ;
        RECT 81.700 98.700 82.300 99.300 ;
        RECT 81.800 89.470 82.200 98.700 ;
        RECT 81.750 88.970 82.250 89.470 ;
        RECT 82.800 88.095 83.200 106.700 ;
        RECT 87.200 104.700 87.800 105.300 ;
        RECT 84.700 94.700 85.300 95.300 ;
        RECT 86.200 94.700 86.800 95.300 ;
        RECT 80.750 87.595 81.250 88.095 ;
        RECT 82.750 87.595 83.250 88.095 ;
        RECT 84.800 87.120 85.200 94.700 ;
        RECT 86.200 90.200 86.800 90.800 ;
        RECT 87.300 88.070 87.700 104.700 ;
        RECT 89.200 101.700 89.800 102.300 ;
        RECT 89.300 89.990 89.700 101.700 ;
        RECT 89.250 89.490 89.750 89.990 ;
        RECT 91.300 88.070 91.700 106.700 ;
        RECT 92.200 95.700 92.800 96.300 ;
        RECT 87.250 87.570 87.750 88.070 ;
        RECT 91.250 87.570 91.750 88.070 ;
        RECT 84.750 86.620 85.250 87.120 ;
        RECT 92.300 86.595 92.700 95.700 ;
        RECT 94.800 88.070 95.200 107.700 ;
        RECT 96.800 90.990 97.200 107.700 ;
        RECT 98.700 95.700 99.300 96.300 ;
        RECT 99.700 95.700 100.300 96.300 ;
        RECT 96.750 90.490 97.250 90.990 ;
        RECT 98.800 88.070 99.200 95.700 ;
        RECT 94.750 87.570 95.250 88.070 ;
        RECT 98.750 87.570 99.250 88.070 ;
        RECT 17.250 86.095 17.750 86.595 ;
        RECT 32.250 86.095 32.750 86.595 ;
        RECT 47.250 86.095 47.750 86.595 ;
        RECT 62.250 86.095 62.750 86.595 ;
        RECT 77.250 86.095 77.750 86.595 ;
        RECT 92.250 86.095 92.750 86.595 ;
        RECT 63.700 85.400 64.300 86.000 ;
        RECT 99.800 85.595 100.200 95.700 ;
        RECT 102.300 88.070 102.700 110.700 ;
        RECT 104.200 107.700 104.800 108.300 ;
        RECT 104.300 90.990 104.700 107.700 ;
        RECT 106.200 95.700 106.800 96.300 ;
        RECT 107.200 95.700 107.800 96.300 ;
        RECT 104.250 90.490 104.750 90.990 ;
        RECT 106.300 88.070 106.700 95.700 ;
        RECT 102.250 87.570 102.750 88.070 ;
        RECT 106.250 87.570 106.750 88.070 ;
        RECT 107.300 85.595 107.700 95.700 ;
        RECT 109.800 88.070 110.200 111.700 ;
        RECT 113.700 110.700 114.300 111.300 ;
        RECT 111.700 106.700 112.300 107.300 ;
        RECT 111.800 90.990 112.200 106.700 ;
        RECT 111.750 90.490 112.250 90.990 ;
        RECT 113.800 88.070 114.200 110.700 ;
        RECT 117.200 109.700 117.800 110.300 ;
        RECT 114.700 95.700 115.300 96.300 ;
        RECT 109.750 87.570 110.250 88.070 ;
        RECT 113.750 87.570 114.250 88.070 ;
        RECT 114.800 85.595 115.200 95.700 ;
        RECT 117.300 88.070 117.700 109.700 ;
        RECT 119.300 90.990 119.700 113.700 ;
        RECT 132.200 111.700 132.800 112.300 ;
        RECT 121.200 110.700 121.800 111.300 ;
        RECT 119.250 90.490 119.750 90.990 ;
        RECT 121.300 88.070 121.700 110.700 ;
        RECT 124.700 109.700 125.300 110.300 ;
        RECT 126.700 109.700 127.300 110.300 ;
        RECT 122.200 95.700 122.800 96.300 ;
        RECT 117.250 87.570 117.750 88.070 ;
        RECT 121.250 87.570 121.750 88.070 ;
        RECT 122.300 85.595 122.700 95.700 ;
        RECT 124.800 88.095 125.200 109.700 ;
        RECT 126.800 90.970 127.200 109.700 ;
        RECT 128.700 94.700 129.300 95.300 ;
        RECT 129.700 94.700 130.300 95.300 ;
        RECT 126.750 90.470 127.250 90.970 ;
        RECT 128.800 88.095 129.200 94.700 ;
        RECT 124.750 87.595 125.250 88.095 ;
        RECT 128.750 87.595 129.250 88.095 ;
        RECT 129.800 85.620 130.200 94.700 ;
        RECT 132.300 88.095 132.700 111.700 ;
        RECT 134.200 109.700 134.800 110.300 ;
        RECT 134.300 90.970 134.700 109.700 ;
        RECT 136.200 94.700 136.800 95.300 ;
        RECT 137.200 94.700 137.800 95.300 ;
        RECT 134.250 90.470 134.750 90.970 ;
        RECT 136.300 88.095 136.700 94.700 ;
        RECT 132.250 87.595 132.750 88.095 ;
        RECT 136.250 87.595 136.750 88.095 ;
        RECT 137.300 85.620 137.700 94.700 ;
        RECT 151.800 91.070 152.200 113.700 ;
        RECT 153.700 107.700 154.300 108.300 ;
        RECT 153.800 103.990 154.200 107.700 ;
        RECT 153.750 103.490 154.250 103.990 ;
        RECT 155.700 95.700 156.300 96.300 ;
        RECT 156.700 95.700 157.300 96.300 ;
        RECT 155.800 91.070 156.200 95.700 ;
        RECT 151.750 90.570 152.250 91.070 ;
        RECT 153.200 90.200 153.800 90.800 ;
        RECT 155.750 90.570 156.250 91.070 ;
        RECT 99.750 85.095 100.250 85.595 ;
        RECT 107.250 85.095 107.750 85.595 ;
        RECT 114.750 85.095 115.250 85.595 ;
        RECT 122.250 85.095 122.750 85.595 ;
        RECT 129.750 85.120 130.250 85.620 ;
        RECT 137.250 85.120 137.750 85.620 ;
        RECT 151.700 85.400 152.300 86.000 ;
        RECT 56.200 84.200 56.800 84.800 ;
        RECT 149.700 84.200 150.300 84.800 ;
        RECT 26.250 83.700 26.750 83.750 ;
        RECT 27.320 83.700 27.920 83.800 ;
        RECT 45.020 83.700 45.620 83.800 ;
        RECT 98.120 83.700 98.720 83.800 ;
        RECT 115.820 83.700 116.420 83.800 ;
        RECT 9.720 83.300 134.020 83.700 ;
        RECT 26.250 83.250 26.750 83.300 ;
        RECT 27.320 83.200 27.920 83.300 ;
        RECT 45.020 83.200 45.620 83.300 ;
        RECT 98.120 83.200 98.720 83.300 ;
        RECT 115.820 83.200 116.420 83.300 ;
        RECT 86.250 82.950 86.750 83.000 ;
        RECT 1.800 82.550 143.200 82.950 ;
        RECT 86.250 82.500 86.750 82.550 ;
        RECT 9.620 82.200 10.220 82.300 ;
        RECT 18.750 82.200 19.250 82.250 ;
        RECT 62.720 82.200 63.320 82.300 ;
        RECT 80.420 82.200 81.020 82.300 ;
        RECT 133.520 82.200 134.120 82.300 ;
        RECT 9.620 81.800 134.120 82.200 ;
        RECT 9.620 81.700 10.220 81.800 ;
        RECT 18.750 81.750 19.250 81.800 ;
        RECT 62.720 81.700 63.320 81.800 ;
        RECT 80.420 81.700 81.020 81.800 ;
        RECT 133.520 81.700 134.120 81.800 ;
        RECT 9.620 63.700 10.220 63.800 ;
        RECT 26.250 63.700 26.750 63.750 ;
        RECT 62.720 63.700 63.320 63.800 ;
        RECT 80.420 63.700 81.020 63.800 ;
        RECT 133.520 63.700 134.120 63.800 ;
        RECT 9.620 63.300 134.120 63.700 ;
        RECT 9.620 63.200 10.220 63.300 ;
        RECT 26.250 63.250 26.750 63.300 ;
        RECT 62.720 63.200 63.320 63.300 ;
        RECT 80.420 63.200 81.020 63.300 ;
        RECT 133.520 63.200 134.120 63.300 ;
        RECT 86.250 62.950 86.750 63.000 ;
        RECT 1.800 62.550 143.200 62.950 ;
        RECT 86.250 62.500 86.750 62.550 ;
        RECT 18.750 62.200 19.250 62.250 ;
        RECT 27.320 62.200 27.920 62.300 ;
        RECT 45.020 62.200 45.620 62.300 ;
        RECT 98.120 62.200 98.720 62.300 ;
        RECT 115.820 62.200 116.420 62.300 ;
        RECT 9.720 61.800 134.020 62.200 ;
        RECT 18.750 61.750 19.250 61.800 ;
        RECT 27.320 61.700 27.920 61.800 ;
        RECT 45.020 61.700 45.620 61.800 ;
        RECT 98.120 61.700 98.720 61.800 ;
        RECT 115.820 61.700 116.420 61.800 ;
        RECT 9.620 43.700 10.220 43.800 ;
        RECT 26.250 43.700 26.750 43.750 ;
        RECT 62.720 43.700 63.320 43.800 ;
        RECT 80.420 43.700 81.020 43.800 ;
        RECT 133.520 43.700 134.120 43.800 ;
        RECT 9.620 43.300 134.120 43.700 ;
        RECT 9.620 43.200 10.220 43.300 ;
        RECT 26.250 43.250 26.750 43.300 ;
        RECT 62.720 43.200 63.320 43.300 ;
        RECT 80.420 43.200 81.020 43.300 ;
        RECT 133.520 43.200 134.120 43.300 ;
        RECT 86.250 42.950 86.750 43.000 ;
        RECT 1.800 42.550 143.200 42.950 ;
        RECT 86.250 42.500 86.750 42.550 ;
        RECT 18.750 42.200 19.250 42.250 ;
        RECT 27.320 42.200 27.920 42.300 ;
        RECT 45.020 42.200 45.620 42.300 ;
        RECT 98.120 42.200 98.720 42.300 ;
        RECT 115.820 42.200 116.420 42.300 ;
        RECT 9.720 41.800 134.020 42.200 ;
        RECT 18.750 41.750 19.250 41.800 ;
        RECT 27.320 41.700 27.920 41.800 ;
        RECT 45.020 41.700 45.620 41.800 ;
        RECT 98.120 41.700 98.720 41.800 ;
        RECT 115.820 41.700 116.420 41.800 ;
        RECT 149.800 40.155 150.200 84.200 ;
        RECT 149.750 39.655 150.250 40.155 ;
        RECT 26.250 23.700 26.750 23.750 ;
        RECT 27.320 23.700 27.920 23.800 ;
        RECT 45.020 23.700 45.620 23.800 ;
        RECT 98.120 23.700 98.720 23.800 ;
        RECT 115.820 23.700 116.420 23.800 ;
        RECT 9.720 23.300 134.020 23.700 ;
        RECT 26.250 23.250 26.750 23.300 ;
        RECT 27.320 23.200 27.920 23.300 ;
        RECT 45.020 23.200 45.620 23.300 ;
        RECT 98.120 23.200 98.720 23.300 ;
        RECT 115.820 23.200 116.420 23.300 ;
        RECT 86.250 22.950 86.750 23.000 ;
        RECT 1.800 22.550 143.200 22.950 ;
        RECT 86.250 22.500 86.750 22.550 ;
        RECT 9.620 22.200 10.220 22.300 ;
        RECT 18.750 22.200 19.250 22.250 ;
        RECT 62.720 22.200 63.320 22.300 ;
        RECT 80.420 22.200 81.020 22.300 ;
        RECT 133.520 22.200 134.120 22.300 ;
        RECT 9.620 21.800 134.120 22.200 ;
        RECT 9.620 21.700 10.220 21.800 ;
        RECT 18.750 21.750 19.250 21.800 ;
        RECT 62.720 21.700 63.320 21.800 ;
        RECT 80.420 21.700 81.020 21.800 ;
        RECT 133.520 21.700 134.120 21.800 ;
        RECT 151.800 6.345 152.200 85.400 ;
        RECT 151.750 5.845 152.250 6.345 ;
        RECT 153.300 5.605 153.700 90.200 ;
        RECT 156.800 78.595 157.200 95.700 ;
        RECT 165.800 91.095 166.200 113.700 ;
        RECT 167.700 111.700 168.300 112.300 ;
        RECT 167.800 101.970 168.200 111.700 ;
        RECT 167.750 101.470 168.250 101.970 ;
        RECT 169.700 94.700 170.300 95.300 ;
        RECT 170.700 94.700 171.300 95.300 ;
        RECT 169.800 91.095 170.200 94.700 ;
        RECT 160.700 90.200 161.300 90.800 ;
        RECT 162.200 90.200 162.800 90.800 ;
        RECT 165.750 90.595 166.250 91.095 ;
        RECT 169.750 90.595 170.250 91.095 ;
        RECT 158.700 85.400 159.300 86.000 ;
        RECT 156.750 78.095 157.250 78.595 ;
        RECT 158.800 40.155 159.200 85.400 ;
        RECT 158.750 39.655 159.250 40.155 ;
        RECT 160.800 6.345 161.200 90.200 ;
        RECT 160.750 5.845 161.250 6.345 ;
        RECT 162.300 5.605 162.700 90.200 ;
        RECT 165.700 87.800 166.300 88.400 ;
        RECT 165.800 74.300 166.200 87.800 ;
        RECT 167.700 86.600 168.300 87.200 ;
        RECT 165.700 73.700 166.300 74.300 ;
        RECT 167.800 31.155 168.200 86.600 ;
        RECT 170.800 80.620 171.200 94.700 ;
        RECT 174.200 90.200 174.800 90.800 ;
        RECT 172.700 87.800 173.300 88.400 ;
        RECT 170.750 80.120 171.250 80.620 ;
        RECT 167.750 30.655 168.250 31.155 ;
        RECT 172.800 13.345 173.200 87.800 ;
        RECT 172.750 12.845 173.250 13.345 ;
        RECT 174.300 12.605 174.700 90.200 ;
        RECT 175.700 89.000 176.300 89.600 ;
        RECT 175.800 40.300 176.200 89.000 ;
        RECT 175.700 39.700 176.300 40.300 ;
        RECT 174.250 12.105 174.750 12.605 ;
        RECT 153.250 5.105 153.750 5.605 ;
        RECT 162.250 5.105 162.750 5.605 ;
        RECT 41.200 3.500 41.800 4.100 ;
        RECT 164.700 3.500 165.300 4.100 ;
        RECT 24.700 2.500 25.300 3.100 ;
        RECT 48.700 2.500 49.300 3.100 ;
        RECT 9.700 1.500 10.300 2.100 ;
        RECT 9.800 0.700 10.200 1.500 ;
        RECT 24.800 0.700 25.200 2.500 ;
        RECT 33.700 1.500 34.300 2.100 ;
        RECT 164.800 0.700 165.200 3.500 ;
        RECT 9.700 0.100 10.300 0.700 ;
        RECT 24.700 0.100 25.300 0.700 ;
        RECT 164.700 0.100 165.300 0.700 ;
      LAYER met3 ;
        RECT 41.200 114.225 41.800 114.300 ;
        RECT 119.200 114.225 119.800 114.300 ;
        RECT 151.700 114.225 152.300 114.300 ;
        RECT 165.700 114.225 166.300 114.300 ;
        RECT 1.775 113.775 178.225 114.225 ;
        RECT 41.200 113.700 41.800 113.775 ;
        RECT 119.200 113.700 119.800 113.775 ;
        RECT 151.700 113.700 152.300 113.775 ;
        RECT 165.700 113.700 166.300 113.775 ;
        RECT 78.700 113.225 79.300 113.300 ;
        RECT 1.775 112.775 178.225 113.225 ;
        RECT 78.700 112.700 79.300 112.775 ;
        RECT 71.200 112.225 71.800 112.300 ;
        RECT 109.700 112.225 110.300 112.300 ;
        RECT 132.200 112.225 132.800 112.300 ;
        RECT 167.700 112.225 168.300 112.300 ;
        RECT 1.775 111.775 178.225 112.225 ;
        RECT 71.200 111.700 71.800 111.775 ;
        RECT 109.700 111.700 110.300 111.775 ;
        RECT 132.200 111.700 132.800 111.775 ;
        RECT 167.700 111.700 168.300 111.775 ;
        RECT 102.200 111.225 102.800 111.300 ;
        RECT 113.700 111.225 114.300 111.300 ;
        RECT 121.200 111.225 121.800 111.300 ;
        RECT 1.775 110.775 178.225 111.225 ;
        RECT 102.200 110.700 102.800 110.775 ;
        RECT 113.700 110.700 114.300 110.775 ;
        RECT 121.200 110.700 121.800 110.775 ;
        RECT 117.200 110.225 117.800 110.300 ;
        RECT 124.700 110.225 125.300 110.300 ;
        RECT 126.700 110.225 127.300 110.300 ;
        RECT 134.200 110.225 134.800 110.300 ;
        RECT 1.775 109.775 178.225 110.225 ;
        RECT 117.200 109.700 117.800 109.775 ;
        RECT 124.700 109.700 125.300 109.775 ;
        RECT 126.700 109.700 127.300 109.775 ;
        RECT 134.200 109.700 134.800 109.775 ;
        RECT 63.700 109.225 64.300 109.300 ;
        RECT 1.775 108.775 178.225 109.225 ;
        RECT 63.700 108.700 64.300 108.775 ;
        RECT 56.200 108.225 56.800 108.300 ;
        RECT 94.700 108.225 95.300 108.300 ;
        RECT 96.700 108.225 97.300 108.300 ;
        RECT 104.200 108.225 104.800 108.300 ;
        RECT 153.700 108.225 154.300 108.300 ;
        RECT 1.775 107.775 178.225 108.225 ;
        RECT 56.200 107.700 56.800 107.775 ;
        RECT 94.700 107.700 95.300 107.775 ;
        RECT 96.700 107.700 97.300 107.775 ;
        RECT 104.200 107.700 104.800 107.775 ;
        RECT 153.700 107.700 154.300 107.775 ;
        RECT 26.200 107.225 26.800 107.300 ;
        RECT 82.700 107.225 83.300 107.300 ;
        RECT 91.200 107.225 91.800 107.300 ;
        RECT 111.700 107.225 112.300 107.300 ;
        RECT 1.775 106.775 178.225 107.225 ;
        RECT 26.200 106.700 26.800 106.775 ;
        RECT 82.700 106.700 83.300 106.775 ;
        RECT 91.200 106.700 91.800 106.775 ;
        RECT 111.700 106.700 112.300 106.775 ;
        RECT 1.600 106.225 2.400 106.400 ;
        RECT 1.600 105.775 178.225 106.225 ;
        RECT 1.600 105.600 2.400 105.775 ;
        RECT 18.700 105.225 19.300 105.300 ;
        RECT 52.700 105.225 53.300 105.300 ;
        RECT 61.200 105.225 61.800 105.300 ;
        RECT 67.700 105.225 68.300 105.300 ;
        RECT 76.200 105.225 76.800 105.300 ;
        RECT 80.700 105.225 81.300 105.300 ;
        RECT 87.200 105.225 87.800 105.300 ;
        RECT 1.775 104.775 178.225 105.225 ;
        RECT 18.700 104.700 19.300 104.775 ;
        RECT 52.700 104.700 53.300 104.775 ;
        RECT 61.200 104.700 61.800 104.775 ;
        RECT 67.700 104.700 68.300 104.775 ;
        RECT 76.200 104.700 76.800 104.775 ;
        RECT 80.700 104.700 81.300 104.775 ;
        RECT 87.200 104.700 87.800 104.775 ;
        RECT 48.700 104.225 49.300 104.300 ;
        RECT 65.700 104.225 66.300 104.300 ;
        RECT 72.200 104.225 72.800 104.300 ;
        RECT 1.775 103.775 178.225 104.225 ;
        RECT 48.700 103.700 49.300 103.775 ;
        RECT 65.700 103.700 66.300 103.775 ;
        RECT 72.200 103.700 72.800 103.775 ;
        RECT 33.700 103.225 34.300 103.300 ;
        RECT 50.700 103.225 51.300 103.300 ;
        RECT 57.200 103.225 57.800 103.300 ;
        RECT 1.775 102.775 178.225 103.225 ;
        RECT 33.700 102.700 34.300 102.775 ;
        RECT 50.700 102.700 51.300 102.775 ;
        RECT 57.200 102.700 57.800 102.775 ;
        RECT 35.700 102.225 36.300 102.300 ;
        RECT 43.200 102.225 43.800 102.300 ;
        RECT 89.200 102.225 89.800 102.300 ;
        RECT 1.775 101.775 178.225 102.225 ;
        RECT 35.700 101.700 36.300 101.775 ;
        RECT 43.200 101.700 43.800 101.775 ;
        RECT 89.200 101.700 89.800 101.775 ;
        RECT 20.700 101.225 21.300 101.300 ;
        RECT 28.200 101.225 28.800 101.300 ;
        RECT 74.200 101.225 74.800 101.300 ;
        RECT 1.775 100.775 178.225 101.225 ;
        RECT 20.700 100.700 21.300 100.775 ;
        RECT 28.200 100.700 28.800 100.775 ;
        RECT 74.200 100.700 74.800 100.775 ;
        RECT 5.700 100.225 6.300 100.300 ;
        RECT 13.200 100.225 13.800 100.300 ;
        RECT 59.200 100.225 59.800 100.300 ;
        RECT 1.775 99.775 178.225 100.225 ;
        RECT 5.700 99.700 6.300 99.775 ;
        RECT 13.200 99.700 13.800 99.775 ;
        RECT 59.200 99.700 59.800 99.775 ;
        RECT 36.700 99.225 37.300 99.300 ;
        RECT 41.700 99.225 42.300 99.300 ;
        RECT 44.200 99.225 44.800 99.300 ;
        RECT 81.700 99.225 82.300 99.300 ;
        RECT 35.775 98.775 84.225 99.225 ;
        RECT 36.700 98.700 37.300 98.775 ;
        RECT 41.700 98.700 42.300 98.775 ;
        RECT 44.200 98.700 44.800 98.775 ;
        RECT 81.700 98.700 82.300 98.775 ;
        RECT 21.700 98.225 22.300 98.300 ;
        RECT 26.700 98.225 27.300 98.300 ;
        RECT 29.200 98.225 29.800 98.300 ;
        RECT 66.700 98.225 67.300 98.300 ;
        RECT 20.775 97.775 69.225 98.225 ;
        RECT 21.700 97.700 22.300 97.775 ;
        RECT 26.700 97.700 27.300 97.775 ;
        RECT 29.200 97.700 29.800 97.775 ;
        RECT 66.700 97.700 67.300 97.775 ;
        RECT 6.700 97.225 7.300 97.300 ;
        RECT 11.700 97.225 12.300 97.300 ;
        RECT 14.200 97.225 14.800 97.300 ;
        RECT 51.700 97.225 52.300 97.300 ;
        RECT 5.775 96.775 54.225 97.225 ;
        RECT 6.700 96.700 7.300 96.775 ;
        RECT 11.700 96.700 12.300 96.775 ;
        RECT 14.200 96.700 14.800 96.775 ;
        RECT 51.700 96.700 52.300 96.775 ;
        RECT 15.200 96.225 15.800 96.300 ;
        RECT 17.200 96.225 17.800 96.300 ;
        RECT 30.200 96.225 30.800 96.300 ;
        RECT 32.200 96.225 32.800 96.300 ;
        RECT 45.200 96.225 45.800 96.300 ;
        RECT 47.200 96.225 47.800 96.300 ;
        RECT 62.200 96.225 62.800 96.300 ;
        RECT 77.200 96.225 77.800 96.300 ;
        RECT 92.200 96.225 92.800 96.300 ;
        RECT 98.700 96.225 99.300 96.300 ;
        RECT 99.700 96.225 100.300 96.300 ;
        RECT 106.200 96.225 106.800 96.300 ;
        RECT 107.200 96.225 107.800 96.300 ;
        RECT 114.700 96.225 115.300 96.300 ;
        RECT 122.200 96.225 122.800 96.300 ;
        RECT 155.700 96.225 156.300 96.300 ;
        RECT 156.700 96.225 157.300 96.300 ;
        RECT 177.600 96.225 178.400 96.400 ;
        RECT 1.775 95.775 178.400 96.225 ;
        RECT 15.200 95.700 15.800 95.775 ;
        RECT 17.200 95.700 17.800 95.775 ;
        RECT 30.200 95.700 30.800 95.775 ;
        RECT 32.200 95.700 32.800 95.775 ;
        RECT 45.200 95.700 45.800 95.775 ;
        RECT 47.200 95.700 47.800 95.775 ;
        RECT 62.200 95.700 62.800 95.775 ;
        RECT 77.200 95.700 77.800 95.775 ;
        RECT 92.200 95.700 92.800 95.775 ;
        RECT 98.700 95.700 99.300 95.775 ;
        RECT 99.700 95.700 100.300 95.775 ;
        RECT 106.200 95.700 106.800 95.775 ;
        RECT 107.200 95.700 107.800 95.775 ;
        RECT 114.700 95.700 115.300 95.775 ;
        RECT 122.200 95.700 122.800 95.775 ;
        RECT 155.700 95.700 156.300 95.775 ;
        RECT 156.700 95.700 157.300 95.775 ;
        RECT 177.600 95.600 178.400 95.775 ;
        RECT 1.600 95.225 2.400 95.400 ;
        RECT 7.700 95.225 8.300 95.300 ;
        RECT 9.700 95.225 10.300 95.300 ;
        RECT 22.700 95.225 23.300 95.300 ;
        RECT 24.700 95.225 25.300 95.300 ;
        RECT 37.700 95.225 38.300 95.300 ;
        RECT 39.700 95.225 40.300 95.300 ;
        RECT 54.700 95.225 55.300 95.300 ;
        RECT 69.700 95.225 70.300 95.300 ;
        RECT 84.700 95.225 85.300 95.300 ;
        RECT 86.200 95.225 86.800 95.300 ;
        RECT 128.700 95.225 129.300 95.300 ;
        RECT 129.700 95.225 130.300 95.300 ;
        RECT 136.200 95.225 136.800 95.300 ;
        RECT 137.200 95.225 137.800 95.300 ;
        RECT 169.700 95.225 170.300 95.300 ;
        RECT 170.700 95.225 171.300 95.300 ;
        RECT 1.600 94.775 178.225 95.225 ;
        RECT 1.600 94.600 2.400 94.775 ;
        RECT 7.700 94.700 8.300 94.775 ;
        RECT 9.700 94.700 10.300 94.775 ;
        RECT 22.700 94.700 23.300 94.775 ;
        RECT 24.700 94.700 25.300 94.775 ;
        RECT 37.700 94.700 38.300 94.775 ;
        RECT 39.700 94.700 40.300 94.775 ;
        RECT 54.700 94.700 55.300 94.775 ;
        RECT 69.700 94.700 70.300 94.775 ;
        RECT 84.700 94.700 85.300 94.775 ;
        RECT 86.200 94.700 86.800 94.775 ;
        RECT 128.700 94.700 129.300 94.775 ;
        RECT 129.700 94.700 130.300 94.775 ;
        RECT 136.200 94.700 136.800 94.775 ;
        RECT 137.200 94.700 137.800 94.775 ;
        RECT 169.700 94.700 170.300 94.775 ;
        RECT 170.700 94.700 171.300 94.775 ;
        RECT 11.600 92.600 12.400 93.400 ;
        RECT 26.600 92.600 27.400 93.400 ;
        RECT 41.600 92.600 42.400 93.400 ;
        RECT 86.200 90.725 86.800 90.800 ;
        RECT 153.200 90.725 153.800 90.800 ;
        RECT 160.700 90.725 161.300 90.800 ;
        RECT 162.200 90.725 162.800 90.800 ;
        RECT 174.200 90.725 174.800 90.800 ;
        RECT 3.775 90.275 177.225 90.725 ;
        RECT 86.200 90.200 86.800 90.275 ;
        RECT 153.200 90.200 153.800 90.275 ;
        RECT 160.700 90.200 161.300 90.275 ;
        RECT 162.200 90.200 162.800 90.275 ;
        RECT 174.200 90.200 174.800 90.275 ;
        RECT 41.200 89.525 41.800 89.600 ;
        RECT 175.700 89.525 176.300 89.600 ;
        RECT 3.775 89.075 177.225 89.525 ;
        RECT 41.200 89.000 41.800 89.075 ;
        RECT 175.700 89.000 176.300 89.075 ;
        RECT 78.700 88.325 79.300 88.400 ;
        RECT 165.700 88.325 166.300 88.400 ;
        RECT 172.700 88.325 173.300 88.400 ;
        RECT 3.775 87.875 177.225 88.325 ;
        RECT 78.700 87.800 79.300 87.875 ;
        RECT 165.700 87.800 166.300 87.875 ;
        RECT 172.700 87.800 173.300 87.875 ;
        RECT 71.200 87.125 71.800 87.200 ;
        RECT 167.700 87.125 168.300 87.200 ;
        RECT 3.775 86.675 177.225 87.125 ;
        RECT 71.200 86.600 71.800 86.675 ;
        RECT 167.700 86.600 168.300 86.675 ;
        RECT 63.700 85.925 64.300 86.000 ;
        RECT 151.700 85.925 152.300 86.000 ;
        RECT 158.700 85.925 159.300 86.000 ;
        RECT 3.775 85.475 177.225 85.925 ;
        RECT 63.700 85.400 64.300 85.475 ;
        RECT 151.700 85.400 152.300 85.475 ;
        RECT 158.700 85.400 159.300 85.475 ;
        RECT 56.200 84.725 56.800 84.800 ;
        RECT 149.700 84.725 150.300 84.800 ;
        RECT 3.775 84.275 177.225 84.725 ;
        RECT 56.200 84.200 56.800 84.275 ;
        RECT 149.700 84.200 150.300 84.275 ;
        RECT 27.220 83.100 28.020 83.900 ;
        RECT 44.920 83.100 45.720 83.900 ;
        RECT 98.020 83.100 98.820 83.900 ;
        RECT 115.720 83.100 116.520 83.900 ;
        RECT 9.520 81.600 10.320 82.400 ;
        RECT 62.620 81.600 63.420 82.400 ;
        RECT 80.320 81.600 81.120 82.400 ;
        RECT 133.420 81.600 134.220 82.400 ;
        RECT 2.720 73.500 18.880 80.200 ;
        RECT 20.420 73.500 36.580 80.200 ;
        RECT 38.120 73.500 54.280 80.200 ;
        RECT 55.820 73.500 71.980 80.200 ;
        RECT 73.520 73.500 89.680 80.200 ;
        RECT 91.220 73.500 107.380 80.200 ;
        RECT 108.920 73.500 125.080 80.200 ;
        RECT 126.620 73.500 142.780 80.200 ;
        RECT 165.600 73.600 166.400 74.400 ;
        RECT 1.500 72.500 143.500 73.500 ;
        RECT 2.720 65.800 18.880 72.500 ;
        RECT 20.420 65.800 36.580 72.500 ;
        RECT 38.120 65.800 54.280 72.500 ;
        RECT 55.820 65.800 71.980 72.500 ;
        RECT 73.520 65.800 89.680 72.500 ;
        RECT 91.220 65.800 107.380 72.500 ;
        RECT 108.920 65.800 125.080 72.500 ;
        RECT 126.620 65.800 142.780 72.500 ;
        RECT 9.520 63.100 10.320 63.900 ;
        RECT 62.620 63.100 63.420 63.900 ;
        RECT 80.320 63.100 81.120 63.900 ;
        RECT 133.420 63.100 134.220 63.900 ;
        RECT 27.220 61.600 28.020 62.400 ;
        RECT 44.920 61.600 45.720 62.400 ;
        RECT 98.020 61.600 98.820 62.400 ;
        RECT 115.720 61.600 116.520 62.400 ;
        RECT 2.720 53.500 18.880 60.200 ;
        RECT 20.420 53.500 36.580 60.200 ;
        RECT 38.120 53.500 54.280 60.200 ;
        RECT 55.820 53.500 71.980 60.200 ;
        RECT 73.520 53.500 89.680 60.200 ;
        RECT 91.220 53.500 107.380 60.200 ;
        RECT 108.920 53.500 125.080 60.200 ;
        RECT 126.620 53.500 142.780 60.200 ;
        RECT 1.500 52.500 143.500 53.500 ;
        RECT 2.720 45.800 18.880 52.500 ;
        RECT 20.420 45.800 36.580 52.500 ;
        RECT 38.120 45.800 54.280 52.500 ;
        RECT 55.820 45.800 71.980 52.500 ;
        RECT 73.520 45.800 89.680 52.500 ;
        RECT 91.220 45.800 107.380 52.500 ;
        RECT 108.920 45.800 125.080 52.500 ;
        RECT 126.620 45.800 142.780 52.500 ;
        RECT 9.520 43.100 10.320 43.900 ;
        RECT 62.620 43.100 63.420 43.900 ;
        RECT 80.320 43.100 81.120 43.900 ;
        RECT 133.420 43.100 134.220 43.900 ;
        RECT 148.420 42.800 176.580 69.200 ;
        RECT 27.220 41.600 28.020 42.400 ;
        RECT 44.920 41.600 45.720 42.400 ;
        RECT 98.020 41.600 98.820 42.400 ;
        RECT 115.720 41.600 116.520 42.400 ;
        RECT 2.720 33.500 18.880 40.200 ;
        RECT 20.420 33.500 36.580 40.200 ;
        RECT 38.120 33.500 54.280 40.200 ;
        RECT 55.820 33.500 71.980 40.200 ;
        RECT 73.520 33.500 89.680 40.200 ;
        RECT 91.220 33.500 107.380 40.200 ;
        RECT 108.920 33.500 125.080 40.200 ;
        RECT 126.620 33.500 142.780 40.200 ;
        RECT 175.600 39.600 176.400 40.400 ;
        RECT 1.500 32.500 143.500 33.500 ;
        RECT 2.720 25.800 18.880 32.500 ;
        RECT 20.420 25.800 36.580 32.500 ;
        RECT 38.120 25.800 54.280 32.500 ;
        RECT 55.820 25.800 71.980 32.500 ;
        RECT 73.520 25.800 89.680 32.500 ;
        RECT 91.220 25.800 107.380 32.500 ;
        RECT 108.920 25.800 125.080 32.500 ;
        RECT 126.620 25.800 142.780 32.500 ;
        RECT 27.220 23.100 28.020 23.900 ;
        RECT 44.920 23.100 45.720 23.900 ;
        RECT 98.020 23.100 98.820 23.900 ;
        RECT 115.720 23.100 116.520 23.900 ;
        RECT 9.520 21.600 10.320 22.400 ;
        RECT 62.620 21.600 63.420 22.400 ;
        RECT 80.320 21.600 81.120 22.400 ;
        RECT 133.420 21.600 134.220 22.400 ;
        RECT 2.720 13.500 18.880 20.200 ;
        RECT 20.420 13.500 36.580 20.200 ;
        RECT 38.120 13.500 54.280 20.200 ;
        RECT 55.820 13.500 71.980 20.200 ;
        RECT 73.520 13.500 89.680 20.200 ;
        RECT 91.220 13.500 107.380 20.200 ;
        RECT 108.920 13.500 125.080 20.200 ;
        RECT 126.620 13.500 142.780 20.200 ;
        RECT 1.500 12.500 143.500 13.500 ;
        RECT 2.720 5.800 18.880 12.500 ;
        RECT 20.420 5.800 36.580 12.500 ;
        RECT 38.120 5.800 54.280 12.500 ;
        RECT 55.820 5.800 71.980 12.500 ;
        RECT 73.520 5.800 89.680 12.500 ;
        RECT 91.220 5.800 107.380 12.500 ;
        RECT 108.920 5.800 125.080 12.500 ;
        RECT 126.620 5.800 142.780 12.500 ;
        RECT 41.200 4.025 41.800 4.100 ;
        RECT 164.700 4.025 165.300 4.100 ;
        RECT 41.200 3.575 165.300 4.025 ;
        RECT 41.200 3.500 41.800 3.575 ;
        RECT 164.700 3.500 165.300 3.575 ;
        RECT 24.700 3.025 25.300 3.100 ;
        RECT 48.700 3.025 49.300 3.100 ;
        RECT 24.700 2.575 49.300 3.025 ;
        RECT 24.700 2.500 25.300 2.575 ;
        RECT 48.700 2.500 49.300 2.575 ;
        RECT 9.700 2.025 10.300 2.100 ;
        RECT 33.700 2.025 34.300 2.100 ;
        RECT 9.700 1.575 34.300 2.025 ;
        RECT 9.700 1.500 10.300 1.575 ;
        RECT 33.700 1.500 34.300 1.575 ;
        RECT 9.600 0.000 10.400 0.800 ;
        RECT 24.600 0.000 25.400 0.800 ;
        RECT 164.600 0.000 165.400 0.800 ;
      LAYER met4 ;
        RECT 11.775 93.400 12.225 114.200 ;
        RECT 26.775 93.400 27.225 114.200 ;
        RECT 41.775 93.400 42.225 114.200 ;
        RECT 177.200 112.700 177.400 114.300 ;
        RECT 178.600 112.700 178.800 114.300 ;
        RECT 11.600 92.600 12.400 93.400 ;
        RECT 26.600 92.600 27.400 93.400 ;
        RECT 41.600 92.600 42.400 93.400 ;
        RECT 27.220 83.100 28.020 83.900 ;
        RECT 44.920 83.100 45.720 83.900 ;
        RECT 98.020 83.100 98.820 83.900 ;
        RECT 115.720 83.100 116.520 83.900 ;
        RECT 9.520 81.600 10.320 82.400 ;
        RECT 9.570 79.805 10.270 81.600 ;
        RECT 3.115 66.195 16.725 79.805 ;
        RECT 18.380 65.860 18.860 80.140 ;
        RECT 27.270 79.805 27.970 83.100 ;
        RECT 19.350 73.400 19.950 78.300 ;
        RECT 19.250 72.600 20.050 73.400 ;
        RECT 9.520 63.100 10.320 63.900 ;
        RECT 9.570 59.805 10.270 63.100 ;
        RECT 3.115 46.195 16.725 59.805 ;
        RECT 18.380 45.860 18.860 60.140 ;
        RECT 19.350 53.400 19.950 72.600 ;
        RECT 20.815 66.195 34.425 79.805 ;
        RECT 36.080 65.860 36.560 80.140 ;
        RECT 44.970 79.805 45.670 83.100 ;
        RECT 62.620 81.600 63.420 82.400 ;
        RECT 80.320 81.600 81.120 82.400 ;
        RECT 37.050 73.400 37.650 78.300 ;
        RECT 36.950 72.600 37.750 73.400 ;
        RECT 27.220 61.600 28.020 62.400 ;
        RECT 27.270 59.805 27.970 61.600 ;
        RECT 19.250 52.600 20.050 53.400 ;
        RECT 9.520 43.100 10.320 43.900 ;
        RECT 9.570 39.805 10.270 43.100 ;
        RECT 3.115 26.195 16.725 39.805 ;
        RECT 18.380 25.860 18.860 40.140 ;
        RECT 19.350 33.400 19.950 52.600 ;
        RECT 20.815 46.195 34.425 59.805 ;
        RECT 36.080 45.860 36.560 60.140 ;
        RECT 37.050 53.400 37.650 72.600 ;
        RECT 38.515 66.195 52.125 79.805 ;
        RECT 53.780 65.860 54.260 80.140 ;
        RECT 62.670 79.805 63.370 81.600 ;
        RECT 54.750 73.400 55.350 78.300 ;
        RECT 54.650 72.600 55.450 73.400 ;
        RECT 44.920 61.600 45.720 62.400 ;
        RECT 44.970 59.805 45.670 61.600 ;
        RECT 36.950 52.600 37.750 53.400 ;
        RECT 27.220 41.600 28.020 42.400 ;
        RECT 27.270 39.805 27.970 41.600 ;
        RECT 19.250 32.600 20.050 33.400 ;
        RECT 9.520 21.600 10.320 22.400 ;
        RECT 9.570 19.805 10.270 21.600 ;
        RECT 3.115 6.195 16.725 19.805 ;
        RECT 18.380 5.860 18.860 20.140 ;
        RECT 19.350 13.400 19.950 32.600 ;
        RECT 20.815 26.195 34.425 39.805 ;
        RECT 36.080 25.860 36.560 40.140 ;
        RECT 37.050 33.400 37.650 52.600 ;
        RECT 38.515 46.195 52.125 59.805 ;
        RECT 53.780 45.860 54.260 60.140 ;
        RECT 54.750 53.400 55.350 72.600 ;
        RECT 56.215 66.195 69.825 79.805 ;
        RECT 71.480 65.860 71.960 80.140 ;
        RECT 80.370 79.805 81.070 81.600 ;
        RECT 72.450 73.400 73.050 78.300 ;
        RECT 72.350 72.600 73.150 73.400 ;
        RECT 62.620 63.100 63.420 63.900 ;
        RECT 62.670 59.805 63.370 63.100 ;
        RECT 54.650 52.600 55.450 53.400 ;
        RECT 44.920 41.600 45.720 42.400 ;
        RECT 44.970 39.805 45.670 41.600 ;
        RECT 36.950 32.600 37.750 33.400 ;
        RECT 27.220 23.100 28.020 23.900 ;
        RECT 27.270 19.805 27.970 23.100 ;
        RECT 19.250 12.600 20.050 13.400 ;
        RECT 19.350 2.700 19.950 12.600 ;
        RECT 20.815 6.195 34.425 19.805 ;
        RECT 36.080 5.860 36.560 20.140 ;
        RECT 37.050 13.400 37.650 32.600 ;
        RECT 38.515 26.195 52.125 39.805 ;
        RECT 53.780 25.860 54.260 40.140 ;
        RECT 54.750 33.400 55.350 52.600 ;
        RECT 56.215 46.195 69.825 59.805 ;
        RECT 71.480 45.860 71.960 60.140 ;
        RECT 72.450 53.400 73.050 72.600 ;
        RECT 73.915 66.195 87.525 79.805 ;
        RECT 89.180 65.860 89.660 80.140 ;
        RECT 98.070 79.805 98.770 83.100 ;
        RECT 90.150 73.400 90.750 78.300 ;
        RECT 90.050 72.600 90.850 73.400 ;
        RECT 80.320 63.100 81.120 63.900 ;
        RECT 80.370 59.805 81.070 63.100 ;
        RECT 72.350 52.600 73.150 53.400 ;
        RECT 62.620 43.100 63.420 43.900 ;
        RECT 62.670 39.805 63.370 43.100 ;
        RECT 54.650 32.600 55.450 33.400 ;
        RECT 44.920 23.100 45.720 23.900 ;
        RECT 44.970 19.805 45.670 23.100 ;
        RECT 36.950 12.600 37.750 13.400 ;
        RECT 37.050 2.700 37.650 12.600 ;
        RECT 38.515 6.195 52.125 19.805 ;
        RECT 53.780 5.860 54.260 20.140 ;
        RECT 54.750 13.400 55.350 32.600 ;
        RECT 56.215 26.195 69.825 39.805 ;
        RECT 71.480 25.860 71.960 40.140 ;
        RECT 72.450 33.400 73.050 52.600 ;
        RECT 73.915 46.195 87.525 59.805 ;
        RECT 89.180 45.860 89.660 60.140 ;
        RECT 90.150 53.400 90.750 72.600 ;
        RECT 91.615 66.195 105.225 79.805 ;
        RECT 106.880 65.860 107.360 80.140 ;
        RECT 115.770 79.805 116.470 83.100 ;
        RECT 133.420 81.600 134.220 82.400 ;
        RECT 107.850 73.400 108.450 78.300 ;
        RECT 107.750 72.600 108.550 73.400 ;
        RECT 98.020 61.600 98.820 62.400 ;
        RECT 98.070 59.805 98.770 61.600 ;
        RECT 90.050 52.600 90.850 53.400 ;
        RECT 80.320 43.100 81.120 43.900 ;
        RECT 80.370 39.805 81.070 43.100 ;
        RECT 72.350 32.600 73.150 33.400 ;
        RECT 62.620 21.600 63.420 22.400 ;
        RECT 62.670 19.805 63.370 21.600 ;
        RECT 54.650 12.600 55.450 13.400 ;
        RECT 54.750 2.700 55.350 12.600 ;
        RECT 56.215 6.195 69.825 19.805 ;
        RECT 71.480 5.860 71.960 20.140 ;
        RECT 72.450 13.400 73.050 32.600 ;
        RECT 73.915 26.195 87.525 39.805 ;
        RECT 89.180 25.860 89.660 40.140 ;
        RECT 90.150 33.400 90.750 52.600 ;
        RECT 91.615 46.195 105.225 59.805 ;
        RECT 106.880 45.860 107.360 60.140 ;
        RECT 107.850 53.400 108.450 72.600 ;
        RECT 109.315 66.195 122.925 79.805 ;
        RECT 124.580 65.860 125.060 80.140 ;
        RECT 133.470 79.805 134.170 81.600 ;
        RECT 125.550 73.400 126.150 78.300 ;
        RECT 125.450 72.600 126.250 73.400 ;
        RECT 115.720 61.600 116.520 62.400 ;
        RECT 115.770 59.805 116.470 61.600 ;
        RECT 107.750 52.600 108.550 53.400 ;
        RECT 98.020 41.600 98.820 42.400 ;
        RECT 98.070 39.805 98.770 41.600 ;
        RECT 90.050 32.600 90.850 33.400 ;
        RECT 80.320 21.600 81.120 22.400 ;
        RECT 80.370 19.805 81.070 21.600 ;
        RECT 72.350 12.600 73.150 13.400 ;
        RECT 72.450 2.700 73.050 12.600 ;
        RECT 73.915 6.195 87.525 19.805 ;
        RECT 89.180 5.860 89.660 20.140 ;
        RECT 90.150 13.400 90.750 32.600 ;
        RECT 91.615 26.195 105.225 39.805 ;
        RECT 106.880 25.860 107.360 40.140 ;
        RECT 107.850 33.400 108.450 52.600 ;
        RECT 109.315 46.195 122.925 59.805 ;
        RECT 124.580 45.860 125.060 60.140 ;
        RECT 125.550 53.400 126.150 72.600 ;
        RECT 127.015 66.195 140.625 79.805 ;
        RECT 142.280 65.860 142.760 80.140 ;
        RECT 165.600 74.350 166.400 74.400 ;
        RECT 161.270 73.650 166.400 74.350 ;
        RECT 161.270 68.805 161.970 73.650 ;
        RECT 165.600 73.600 166.400 73.650 ;
        RECT 133.420 63.100 134.220 63.900 ;
        RECT 133.470 59.805 134.170 63.100 ;
        RECT 125.450 52.600 126.250 53.400 ;
        RECT 115.720 41.600 116.520 42.400 ;
        RECT 115.770 39.805 116.470 41.600 ;
        RECT 107.750 32.600 108.550 33.400 ;
        RECT 98.020 23.100 98.820 23.900 ;
        RECT 98.070 19.805 98.770 23.100 ;
        RECT 90.050 12.600 90.850 13.400 ;
        RECT 90.150 2.700 90.750 12.600 ;
        RECT 91.615 6.195 105.225 19.805 ;
        RECT 106.880 5.860 107.360 20.140 ;
        RECT 107.850 13.400 108.450 32.600 ;
        RECT 109.315 26.195 122.925 39.805 ;
        RECT 124.580 25.860 125.060 40.140 ;
        RECT 125.550 33.400 126.150 52.600 ;
        RECT 127.015 46.195 140.625 59.805 ;
        RECT 142.280 45.860 142.760 60.140 ;
        RECT 133.420 43.100 134.220 43.900 ;
        RECT 148.815 43.195 174.425 68.805 ;
        RECT 176.080 56.350 176.560 69.140 ;
        RECT 133.470 39.805 134.170 43.100 ;
        RECT 175.970 40.400 176.670 56.350 ;
        RECT 125.450 32.600 126.250 33.400 ;
        RECT 115.720 23.100 116.520 23.900 ;
        RECT 115.770 19.805 116.470 23.100 ;
        RECT 107.750 12.600 108.550 13.400 ;
        RECT 107.850 2.700 108.450 12.600 ;
        RECT 109.315 6.195 122.925 19.805 ;
        RECT 124.580 5.860 125.060 20.140 ;
        RECT 125.550 13.400 126.150 32.600 ;
        RECT 127.015 26.195 140.625 39.805 ;
        RECT 142.280 25.860 142.760 40.140 ;
        RECT 175.600 39.650 176.670 40.400 ;
        RECT 175.600 39.600 176.400 39.650 ;
        RECT 133.420 21.600 134.220 22.400 ;
        RECT 133.470 19.805 134.170 21.600 ;
        RECT 125.450 12.600 126.250 13.400 ;
        RECT 125.550 2.700 126.150 12.600 ;
        RECT 127.015 6.195 140.625 19.805 ;
        RECT 142.280 5.860 142.760 20.140 ;
        RECT 1.200 0.700 1.400 2.300 ;
        RECT 2.600 0.700 2.800 2.300 ;
        RECT 9.600 0.000 9.700 0.800 ;
        RECT 10.300 0.000 10.400 0.800 ;
        RECT 24.600 0.000 24.700 0.800 ;
        RECT 25.300 0.000 25.400 0.800 ;
        RECT 164.600 0.000 164.700 0.800 ;
        RECT 165.300 0.000 165.400 0.800 ;
      LAYER met5 ;
        RECT 0.000 112.700 180.000 114.300 ;
        RECT 0.000 0.700 180.000 2.300 ;
  END
END silicluster_jonah_2cap_dac
END LIBRARY

